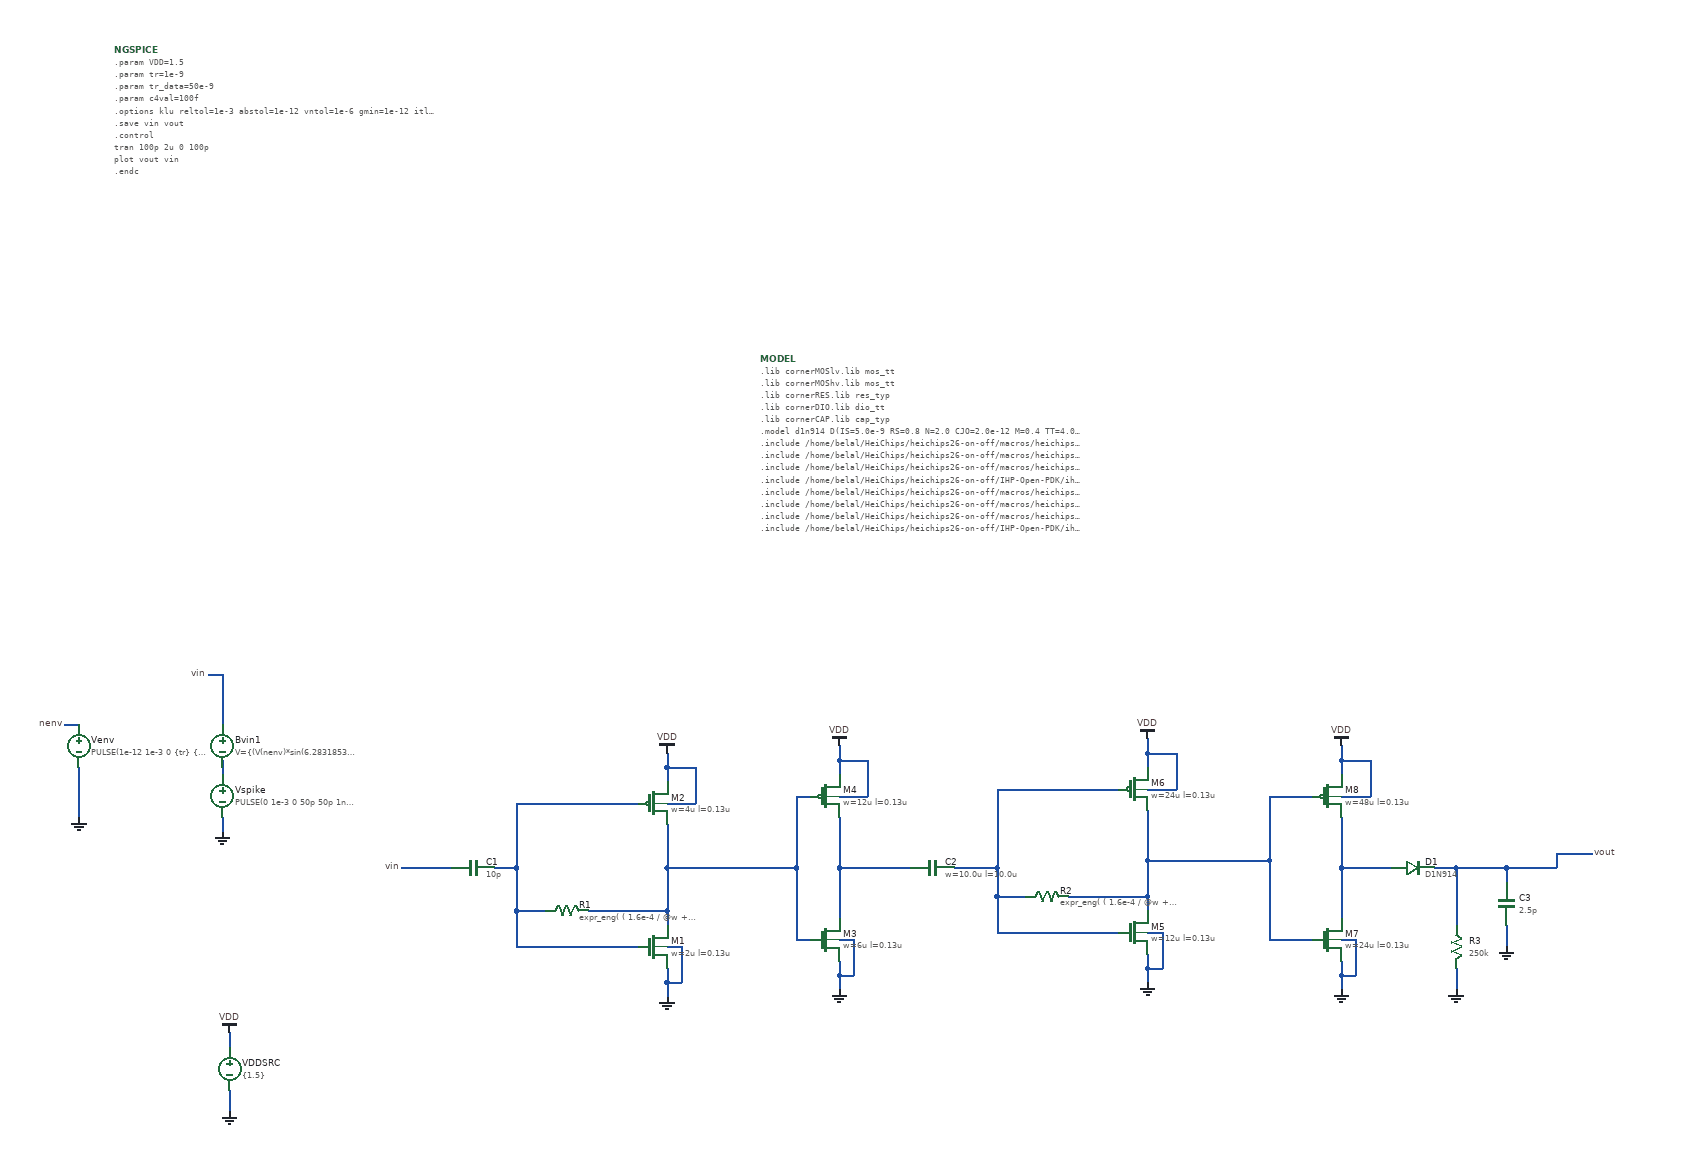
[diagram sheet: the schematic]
v {xschem version=3.4.8RC file_version=1.3}
G {}
K {}
V {}
S {}
F {}
E {}
N 160 -800 160 -780 {lab=VDD}
N 160 -720 160 -690 {lab=GND}
N 770 -970 770 -950 {lab=#net1}
N 560 -920 730 -920 {lab=#net2}
N 560 -970 560 -920 {lab=#net2}
N 560 -1120 730 -1120 {lab=#net2}
N 660 -970 770 -970 {lab=#net1}
N 770 -1030 770 -970 {lab=#net1}
N 560 -970 600 -970 {lab=#net2}
N 560 -1030 560 -970 {lab=#net2}
N 770 -870 770 -850 {lab=GND}
N 770 -1170 770 -1150 {lab=VDD}
N 770 -1120 810 -1120 {lab=VDD}
N 770 -1170 810 -1170 {lab=VDD}
N 770 -1190 770 -1170 {lab=VDD}
N 810 -1170 810 -1120 {lab=VDD}
N 770 -920 790 -920 {lab=GND}
N 790 -920 790 -870 {lab=GND}
N 770 -870 790 -870 {lab=GND}
N 770 -890 770 -870 {lab=GND}
N 530 -1030 560 -1030 {lab=#net2}
N 560 -1120 560 -1030 {lab=#net2}
N 400 -1030 470 -1030 {lab=vin}
N 770 -1030 950 -1030 {lab=#net1}
N 770 -1090 770 -1030 {lab=#net1}
N 130 -1300 150 -1300 {lab=vin}
N 150 -1300 150 -1230 {lab=vin}
N 150 -1180 150 -1160 {lab=#net3}
N 1010 -880 1010 -860 {lab=GND}
N 1010 -1180 1010 -1160 {lab=VDD}
N 1010 -1130 1050 -1130 {lab=VDD}
N 1010 -1180 1050 -1180 {lab=VDD}
N 1010 -1200 1010 -1180 {lab=VDD}
N 1050 -1180 1050 -1130 {lab=VDD}
N 1010 -930 1030 -930 {lab=GND}
N 1030 -930 1030 -880 {lab=GND}
N 1010 -880 1030 -880 {lab=GND}
N 1010 -900 1010 -880 {lab=GND}
N 1010 -1030 1010 -960 {lab=#net4}
N 950 -1130 950 -1030 {lab=#net1}
N 950 -1130 970 -1130 {lab=#net1}
N 950 -930 970 -930 {lab=#net1}
N 950 -1030 950 -930 {lab=#net1}
N 1440 -990 1440 -970 {lab=#net5}
N 1230 -990 1230 -940 {lab=#net6}
N 1230 -1140 1400 -1140 {lab=#net6}
N 1330 -990 1440 -990 {lab=#net5}
N 1230 -990 1270 -990 {lab=#net6}
N 1440 -890 1440 -870 {lab=GND}
N 1440 -1190 1440 -1170 {lab=VDD}
N 1440 -1140 1480 -1140 {lab=VDD}
N 1440 -1190 1480 -1190 {lab=VDD}
N 1440 -1210 1440 -1190 {lab=VDD}
N 1480 -1190 1480 -1140 {lab=VDD}
N 1440 -940 1460 -940 {lab=GND}
N 1460 -940 1460 -890 {lab=GND}
N 1440 -890 1460 -890 {lab=GND}
N 1440 -910 1440 -890 {lab=GND}
N 1230 -1030 1230 -990 {lab=#net6}
N 1440 -1040 1440 -990 {lab=#net5}
N 1170 -1030 1230 -1030 {lab=#net6}
N 1230 -1140 1230 -1030 {lab=#net6}
N 1010 -1030 1110 -1030 {lab=#net4}
N 1010 -1100 1010 -1030 {lab=#net4}
N 1710 -880 1710 -860 {lab=GND}
N 1710 -1180 1710 -1160 {lab=VDD}
N 1710 -1130 1750 -1130 {lab=VDD}
N 1710 -1180 1750 -1180 {lab=VDD}
N 1710 -1200 1710 -1180 {lab=VDD}
N 1750 -1180 1750 -1130 {lab=VDD}
N 1710 -930 1730 -930 {lab=GND}
N 1730 -930 1730 -880 {lab=GND}
N 1710 -880 1730 -880 {lab=GND}
N 1710 -900 1710 -880 {lab=GND}
N 1610 -930 1670 -930 {lab=#net5}
N 1610 -1130 1670 -1130 {lab=#net5}
N 1610 -1040 1610 -930 {lab=#net5}
N 1610 -1130 1610 -1040 {lab=#net5}
N 1440 -1040 1610 -1040 {lab=#net5}
N 1440 -1110 1440 -1040 {lab=#net5}
N 2010 -1050 2060 -1050 {lab=vout}
N 1710 -1030 1710 -960 {lab=#net7}
N 150 -1100 150 -1080 {lab=GND}
N 1230 -940 1400 -940 {lab=#net6}
N 1710 -1030 1780 -1030 {lab=#net7}
N 1710 -1100 1710 -1030 {lab=#net7}
N 1940 -1030 2010 -1030 {lab=vout}
N 2010 -1050 2010 -1030 {lab=vout}
N 1940 -1030 1940 -1010 {lab=vout}
N 1870 -1030 1940 -1030 {lab=vout}
N 1870 -1030 1870 -950 {lab=vout}
N 1840 -1030 1870 -1030 {lab=vout}
N 1940 -950 1940 -920 {lab=GND}
N 1870 -890 1870 -860 {lab=GND}
N -70 -1230 -50 -1230 {lab=nenv}
N -50 -1170 -50 -1100 {lab=GND}
C {devices/code_shown.sym} 0 -2170 0 0 {name=NGSPICE
only_toplevel=true
value="
.param VDD=1.5
.param tr=1e-9
.param tr_data=50e-9
.param c4val=100f
.options klu reltol=1e-3 abstol=1e-12 vntol=1e-6 gmin=1e-12 itl1=200 itl4=100 rshunt=1e9 trtol=20
.save vin vout
.control
tran 100p 2u 0 100p
plot vout vin
.endc
"}
C {devices/launcher.sym} 2300 -1410 0 0 {name=h2
descr="Simulate"
tclcommand="xschem save; xschem netlist; xschem simulate"
}
C {title-3.sym} 0 0 0 0 {name=l2 author="Belal Elshinnawey" rev=1.0 lock=true}
C {devices/launcher.sym} 2300 -1350 0 0 {name=h3
descr="Annotate OP"
tclcommand="set show_hidden_texts 1; xschem annotate_op"
}
C {devices/code_shown.sym} 900 -1740 0 0 {name=MODEL only_toplevel=true
format="tcleval( @value )"
value="
.lib cornerMOSlv.lib mos_tt
.lib cornerMOShv.lib mos_tt
.lib cornerRES.lib res_typ
.lib cornerDIO.lib dio_tt
.lib cornerCAP.lib cap_typ
.model d1n914 D(IS=5.0e-9 RS=0.8 N=2.0 CJO=2.0e-12 M=0.4 TT=4.0e-9 BV=100 IBV=1e-4 EG=1.11 XTI=3)
.include /home/belal/HeiChips/heichips26-on-off/macros/heichips26_ook_top/macros/dac/netlist/xspice/dac.xspice
.include /home/belal/HeiChips/heichips26-on-off/macros/heichips26_ook_top/macros/ook_analog_system/netlist/pex/ook_transmitter_magic_pex_3.spice
.include /home/belal/HeiChips/heichips26-on-off/macros/heichips26_ook_top/macros/ook_analog_system/netlist/pex/ook_analog_system_magic_pex_3.spice
.include /home/belal/HeiChips/heichips26-on-off/IHP-Open-PDK/ihp-sg13cmos5l/libs.tech/ngspice/models/cap_mfringe.lib
.include /home/belal/HeiChips/heichips26-on-off/macros/heichips26_ook_top/macros/ook_analog_system/netlist/pex/vco_magic_pex_3.spice
.include /home/belal/HeiChips/heichips26-on-off/macros/heichips26_ook_top/macros/ook_analog_system/netlist/pex/output_buffer_magic_pex_3.spice
.include /home/belal/HeiChips/heichips26-on-off/macros/heichips26_ook_top/netlist/pex/heichips26_ook_top_magic_pex_3.spice
.include /home/belal/HeiChips/heichips26-on-off/IHP-Open-PDK/ihp-sg13cmos5l/libs.ref/sg13cmos5l_io/spice/sg13cmos5l_io.spi
"}
C {devices/vsource.sym} 160 -750 0 0 {name=VDDSRC value=\{1.5\}}
C {vdd.sym} 160 -800 0 0 {name=lvddb lab=VDD}
C {devices/gnd.sym} 160 -690 0 0 {name=lgnd5 lab=GND}
C {sg13cmos5l_pr/sg13_lv_nmos.sym} 750 -920 0 0 {name=M1
l=0.13u
w=2u
ng=1
m=1
mm_ok=1
model=sg13_lv_nmos
spiceprefix=X
}
C {sg13cmos5l_pr/sg13_lv_pmos.sym} 750 -1120 0 0 {name=M2
l=0.13u
w=4u
ng=1
m=1
mm_ok=1
model=sg13_lv_pmos
spiceprefix=X
}
C {sg13cmos5l_pr/rhigh.sym} 630 -970 3 0 {name=R1
w=2e-6
l=3.85e-6
model=rhigh
body=GND
spiceprefix=X
b=0
 m=1
  mm_ok=1
value="expr_eng(  ( 1.6e-4 / @w + 1360.0 * ( (@b + 1)* @l + ( 1.081*( @w - 0.04e-6 ) + 0.18e-6 )*@b ) / ( @w - 0.04e-6 ) ) / @m  )"
}
C {devices/gnd.sym} 770 -850 0 0 {name=lgnd1 lab=GND}
C {vdd.sym} 770 -1190 0 0 {name=lvddb1 lab=VDD}
C {capa.sym} 500 -1030 3 0 {name=C1
m=1
value=10p
footprint=1206
device="ceramic capacitor"}
C {lab_pin.sym} 400 -1030 0 0 {name=p1 sig_type=std_logic lab=vin}
C {devices/vsource.sym} 150 -1200 0 0 {name=Bvin1 value="V=\{(V(nenv)*sin(6.283185307*433.92e6*time))\}"}
C {devices/vsource.sym} -50 -1200 0 0 {name=Venv value="PULSE(1e-12 1e-3 0 \{tr\} \{tr\} 1e-6 10)"}
C {devices/gnd.sym} -50 -1100 0 0 {name=lgnd_env lab=GND}
C {lab_pin.sym} -70 -1230 0 0 {name=p_env sig_type=std_logic lab=nenv}
C {lab_pin.sym} 130 -1300 0 0 {name=p3 sig_type=std_logic lab=vin}
C {devices/gnd.sym} 150 -1080 0 0 {name=lgnd2 lab=GND}
C {devices/vsource.sym} 150 -1130 0 0 {name=Vspike value="PULSE(0 1e-3 0 50p 50p 1n 6.25n)"}
C {sg13cmos5l_pr/sg13_lv_nmos.sym} 990 -930 0 0 {name=M3
l=0.13u
w=6u
ng=3
m=1
mm_ok=1
model=sg13_lv_nmos
spiceprefix=X
}
C {sg13cmos5l_pr/sg13_lv_pmos.sym} 990 -1130 0 0 {name=M4
l=0.13u
w=12u
ng=3
m=1
mm_ok=1
model=sg13_lv_pmos
spiceprefix=X
}
C {devices/gnd.sym} 1010 -860 0 0 {name=lgnd3 lab=GND}
C {vdd.sym} 1010 -1200 0 0 {name=lvddb2 lab=VDD}
C {lab_pin.sym} 2060 -1050 2 0 {name=p4 sig_type=std_logic lab=vout}
C {sg13cmos5l_pr/sg13_lv_nmos.sym} 1420 -940 0 0 {name=M5
l=0.13u
w=12u
ng=3
m=1
mm_ok=1
model=sg13_lv_nmos
spiceprefix=X
}
C {sg13cmos5l_pr/sg13_lv_pmos.sym} 1420 -1140 0 0 {name=M6
l=0.13u
w=24u
ng=10
m=1
mm_ok=1
model=sg13_lv_pmos
spiceprefix=X
}
C {sg13cmos5l_pr/rhigh.sym} 1300 -990 3 0 {name=R2
w=2e-6
l=3.85e-6
model=rhigh
body=GND
spiceprefix=X
b=0
 m=1
  mm_ok=1
value="expr_eng(  ( 1.6e-4 / @w + 1360.0 * ( (@b + 1)* @l + ( 1.081*( @w - 0.04e-6 ) + 0.18e-6 )*@b ) / ( @w - 0.04e-6 ) ) / @m  )"
}
C {devices/gnd.sym} 1440 -870 0 0 {name=lgnd6 lab=GND}
C {vdd.sym} 1440 -1210 0 0 {name=lvddb3 lab=VDD}
C {sg13cmos5l_pr/cap_mfringe.sym} 1140 -1030 1 0 {name=C2
model=cap_mfringe
w=10.0u
l=10.0u
mmin=3
mmax=4
spiceprefix=X
}
C {sg13cmos5l_pr/sg13_lv_nmos.sym} 1690 -930 0 0 {name=M7
l=0.13u
w=24u
ng=10
m=1
mm_ok=1
model=sg13_lv_nmos
spiceprefix=X
}
C {sg13cmos5l_pr/sg13_lv_pmos.sym} 1690 -1130 0 0 {name=M8
l=0.13u
w=48u
ng=20
m=1
mm_ok=1
model=sg13_lv_pmos
spiceprefix=X
}
C {devices/gnd.sym} 1710 -860 0 0 {name=lgnd7 lab=GND}
C {vdd.sym} 1710 -1200 0 0 {name=lvddb5 lab=VDD}
C {diode.sym} 1810 -1030 3 0 {name=D1 model=D1N914 area=1}
C {capa.sym} 1940 -980 0 0 {name=C3
m=1
value=2.5p
footprint=1206
device="ceramic capacitor"}
C {res.sym} 1870 -920 2 1 {name=R3
value=250k
int=1206
device=resistor
m=1}
C {devices/gnd.sym} 1870 -860 0 0 {name=lgnd9 lab=GND}
C {devices/gnd.sym} 1940 -920 0 0 {name=lgnd10 lab=GND}
